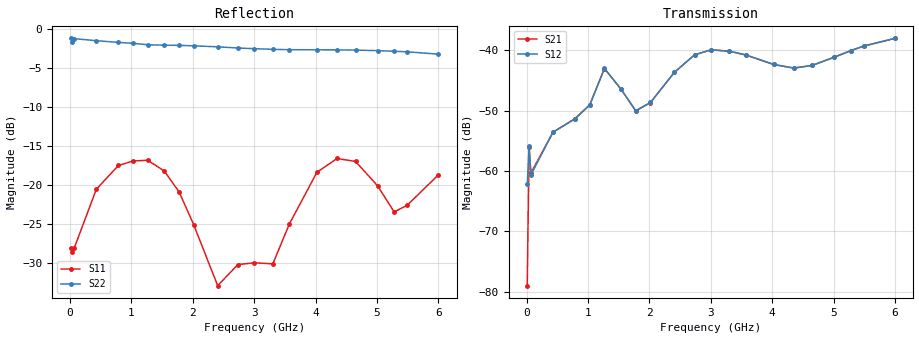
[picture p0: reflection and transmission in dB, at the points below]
!Agilent Technologies,E8364B,MY43040528,A.07.50.67
!Agilent E8364B: A.07.50.67
!Date: Sunday, September 28, 2025 21:31:18
!Correction: S11(Full 2 Port(1,2))
!S21(Full 2 Port(1,2))
!S12(Full 2 Port(1,2))
!S22(Full 2 Port(1,2))
!S2P File: Measurements: S11, S21, S12, S22:
# Hz S  dB  R 50
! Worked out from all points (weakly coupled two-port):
!   201 points, 10 MHz to 6 GHz, reference 50 ohm
!   highest |S21| = -38.04 dB at 6 GHz (marker M1); lowest = -79.0 dB at 10 MHz (marker M2)
!   lowest |S11| = -33.0 dB at 2.406 GHz (marker M3), VSWR 1.05, Z = 50.1 + j2.24 ohm
!   |S11| at or under -10 dB: start of sweep to end of sweep
!   |S22| runs from -3.2 to -1.2 dB; largest |S21 - S12| = 0.00074
!   S11 on the Smith chart (normalised r, x): 10 MHz: 1.07, -0.04; 788.7 MHz: 0.77, -0.05; 1.537 GHz: 0.92, +0.22; 4.652 GHz: 1.24, +0.21; 6 GHz: 1.24, -0.10
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1e7  -28.13 -31.3  -79.01 107.5  -62.24 38.2  -1.15 -180.0
3.995e7  -28.64 -21.3  -56.08 17.4  -55.95 14.3  -1.56 -177.0
6.99e7  -28.13 -27.7  -60.33 12.9  -60.67 10.7  -1.19 174.4
4.293e8  -20.57 -113.4  -53.59 -1.7  -53.59 -2.2  -1.45 130.4
7.887e8  -17.51 -167.1  -51.32 -44.8  -51.38 -45.0  -1.67 89.7
1.0283e9  -16.93 164.2  -49.06 -61.9  -49.05 -61.8  -1.79 62.6
1.2679e9  -16.84 135.8  -43.04 -125.0  -43.03 -125.0  -1.97 35.9
1.53745e9  -18.23 103.3  -46.45 138.1  -46.45 138.2  -2.03 6.0
1.77705e9  -20.90 78.3  -50.04 64.0  -50.04 64.1  -2.05 -21.9
2.01665e9  -25.15 60.9  -48.69 -12.3  -48.66 -12.1  -2.11 -50.4
2.406e9  -32.98 85.2  -43.67 -105.6  -43.68 -105.5  -2.24 -97.8
2.73545e9  -30.26 106.5  -40.78 -170.0  -40.76 -170.0  -2.39 -138.2
3.005e9  -30.03 105.2  -39.94 140.2  -39.94 140.3  -2.48 -171.3
3.3045e9  -30.17 124.3  -40.17 91.9  -40.17 92.0  -2.56 151.9
3.57405e9  -25.04 134.9  -40.80 53.9  -40.80 53.9  -2.61 119.2
4.0233e9  -18.38 102.4  -42.36 0.6  -42.36 0.6  -2.62 66.5
4.35275e9  -16.61 67.7  -42.97 -29.4  -42.96 -29.4  -2.63 29.0
4.65225e9  -16.99 36.2  -42.51 -55.7  -42.52 -55.7  -2.66 -4.6
5.01165e9  -20.13 6.9  -41.16 -92.2  -41.15 -92.1  -2.73 -44.8
5.2812e9  -23.49 8.6  -40.07 -123.5  -40.07 -123.4  -2.81 -75.2
5.49085e9  -22.65 20.6  -39.31 -149.7  -39.32 -149.7  -2.88 -99.1
6e9  -18.73 -19.2  -38.04 141.4  -38.04 141.4  -3.18 -159.2
